VERSION 5.8 ;
BUSBITCHARS "[]" ;
DIVIDERCHAR "/" ;
UNITS
    DATABASE MICRONS 1000 ;
END UNITS

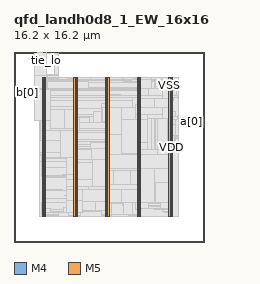
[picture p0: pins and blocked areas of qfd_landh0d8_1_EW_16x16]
MACRO qfd_landh0d8_1_EW_16x16
  FOREIGN qfd_landh0d8_1_EW_16x16 0 0 ;
  CLASS BLOCK ;
  SIZE 16.2 BY 16.2 ;
  PIN a[0]
    DIRECTION INPUT ;
    USE SIGNAL ;
    PORT
      LAYER M4 ;
        RECT  16.116 10.224 16.2 10.248 ;
    END
    PORT
      LAYER M4 ;
        RECT  15.397 10.224 16.14 10.248 ;
    END
  END a[0]
  PIN b[0]
    DIRECTION OUTPUT ;
    USE SIGNAL ;
    PORT
      LAYER M4 ;
        RECT  0 12.72 0.084 12.744 ;
    END
    PORT
      LAYER M4 ;
        RECT  0.06 12.72 1.861 12.744 ;
    END
  END b[0]
  PIN ck
    DIRECTION INPUT ;
    USE SIGNAL ;
    PORT
      LAYER M5 ;
        RECT  1.776 16.116 1.8 16.2 ;
    END
  END ck
  PIN ck_s
    DIRECTION INPUT ;
    USE SIGNAL ;
    PORT
      LAYER M5 ;
        RECT  1.872 16.116 1.896 16.2 ;
    END
  END ck_s
  PIN en
    DIRECTION INPUT ;
    USE SIGNAL ;
    PORT
      LAYER M5 ;
        RECT  1.968 16.116 1.992 16.2 ;
    END
  END en
  PIN fault
    DIRECTION OUTPUT ;
    USE SIGNAL ;
    PORT
      LAYER M5 ;
        RECT  2.064 16.116 2.088 16.2 ;
    END
  END fault
  PIN k0
    DIRECTION INPUT ;
    USE SIGNAL ;
    PORT
      LAYER M5 ;
        RECT  2.16 16.116 2.184 16.2 ;
    END
  END k0
  PIN k1
    DIRECTION INPUT ;
    USE SIGNAL ;
    PORT
      LAYER M5 ;
        RECT  2.256 16.116 2.28 16.2 ;
    END
  END k1
  PIN k2
    DIRECTION INPUT ;
    USE SIGNAL ;
    PORT
      LAYER M5 ;
        RECT  2.352 16.116 2.376 16.2 ;
    END
  END k2
  PIN k3
    DIRECTION INPUT ;
    USE SIGNAL ;
    PORT
      LAYER M5 ;
        RECT  2.448 16.116 2.472 16.2 ;
    END
  END k3
  PIN rs
    DIRECTION INPUT ;
    USE SIGNAL ;
    PORT
      LAYER M5 ;
        RECT  2.544 16.116 2.568 16.2 ;
    END
  END rs
  PIN tie_hi
    DIRECTION OUTPUT ;
    USE SIGNAL ;
    PORT
      LAYER M5 ;
        RECT  2.64 16.116 2.664 16.2 ;
    END
  END tie_hi
  PIN tie_lo
    DIRECTION OUTPUT ;
    USE SIGNAL ;
    PORT
      LAYER M5 ;
        RECT  2.736 16.116 2.76 16.2 ;
    END
  END tie_lo
  PIN VDD
    DIRECTION INOUT ;
    USE POWER ;
    PORT
      LAYER M5 ;
        RECT  13.392 2.151 13.512 14.049 ;
        RECT  10.692 2.151 10.812 14.049 ;
        RECT  7.992 2.151 8.112 14.049 ;
        RECT  5.292 2.151 5.412 14.049 ;
        RECT  2.592 2.151 2.712 14.049 ;
    END
  END VDD
  PIN VSS
    DIRECTION INOUT ;
    USE GROUND ;
    PORT
      LAYER M5 ;
        RECT  13.2 2.137 13.32 14.063 ;
        RECT  10.5 2.137 10.62 14.063 ;
        RECT  7.8 2.137 7.92 14.063 ;
        RECT  5.1 2.137 5.22 14.063 ;
        RECT  2.4 2.137 2.52 14.063 ;
    END
  END VSS
  # OT_OBS_CLOSED layer=M5 d_um=1.536 added=28
  OBS
    LAYER RVTN ;
     RECT  2.16 2.16 14.04 2.295 ;
     RECT  2.16 2.565 14.04 2.835 ;
     RECT  2.16 3.105 14.04 3.375 ;
     RECT  2.16 3.645 14.04 3.915 ;
     RECT  2.16 4.185 14.04 4.455 ;
     RECT  2.16 4.725 14.04 4.995 ;
     RECT  2.16 5.265 14.04 5.535 ;
     RECT  2.16 5.805 14.04 6.075 ;
     RECT  2.16 6.345 14.04 6.615 ;
     RECT  2.16 6.885 14.04 7.155 ;
     RECT  2.16 7.425 14.04 7.695 ;
     RECT  2.16 7.965 14.04 8.235 ;
     RECT  2.16 8.505 14.04 8.775 ;
     RECT  2.16 9.045 14.04 9.315 ;
     RECT  2.16 9.585 14.04 9.855 ;
     RECT  2.16 10.125 14.04 10.395 ;
     RECT  2.16 10.665 14.04 10.935 ;
     RECT  2.16 11.205 14.04 11.475 ;
     RECT  2.16 11.745 14.04 12.015 ;
     RECT  2.16 12.285 14.04 12.555 ;
     RECT  2.16 12.825 14.04 13.095 ;
     RECT  2.16 13.365 14.04 13.635 ;
     RECT  2.16 13.905 14.04 14.04 ;
    LAYER RVTP ;
     RECT  2.16 2.295 14.04 2.565 ;
     RECT  2.16 2.835 14.04 3.105 ;
     RECT  2.16 3.375 14.04 3.645 ;
     RECT  2.16 3.915 14.04 4.185 ;
     RECT  2.16 4.455 14.04 4.725 ;
     RECT  2.16 4.995 14.04 5.265 ;
     RECT  2.16 5.535 14.04 5.805 ;
     RECT  2.16 6.075 14.04 6.345 ;
     RECT  2.16 6.615 14.04 6.885 ;
     RECT  2.16 7.155 14.04 7.425 ;
     RECT  2.16 7.695 14.04 7.965 ;
     RECT  2.16 8.235 14.04 8.505 ;
     RECT  2.16 8.775 14.04 9.045 ;
     RECT  2.16 9.315 14.04 9.585 ;
     RECT  2.16 9.855 14.04 10.125 ;
     RECT  2.16 10.395 14.04 10.665 ;
     RECT  2.16 10.935 14.04 11.205 ;
     RECT  2.16 11.475 14.04 11.745 ;
     RECT  2.16 12.015 14.04 12.285 ;
     RECT  2.16 12.555 14.04 12.825 ;
     RECT  2.16 13.095 14.04 13.365 ;
     RECT  2.16 13.635 14.04 13.905 ;
    LAYER M1 ;
     RECT  2.16 2.151 14.04 14.049 ;
    LAYER M2 ;
     RECT  2.16 2.151 14.04 14.049 ;
     RECT  14.04 10.17 15.431 10.188 ;
    LAYER M3 ;
     RECT  2.415 2.143 2.505 2.191 ;
     RECT  5.115 2.143 5.205 2.191 ;
     RECT  10.515 2.143 10.605 2.191 ;
     RECT  5.115 2.191 5.634 2.227 ;
     RECT  7.815 2.143 7.905 2.227 ;
     RECT  10.224 2.191 10.605 2.227 ;
     RECT  2.415 2.191 2.574 2.299 ;
     RECT  3.816 2.227 3.834 2.299 ;
     RECT  7.488 2.227 8.154 2.299 ;
     RECT  2.415 2.299 3.834 2.371 ;
     RECT  9.756 2.227 10.605 2.413 ;
     RECT  13.215 2.143 13.305 2.413 ;
     RECT  2.376 2.371 3.834 2.491 ;
     RECT  13.215 2.413 13.497 2.533 ;
     RECT  12.816 2.533 13.497 2.569 ;
     RECT  2.376 2.491 3.942 2.641 ;
     RECT  4.68 2.227 5.634 2.641 ;
     RECT  6.732 2.605 6.75 2.641 ;
     RECT  7.488 2.299 8.334 2.641 ;
     RECT  9.756 2.413 10.797 2.641 ;
     RECT  9.72 2.641 10.797 2.731 ;
     RECT  12.636 2.569 13.497 2.731 ;
     RECT  2.376 2.641 8.334 2.759 ;
     RECT  9.72 2.731 10.854 2.839 ;
     RECT  9.504 2.839 10.854 2.875 ;
     RECT  11.988 2.731 13.497 2.875 ;
     RECT  9.396 2.875 13.497 3.001 ;
     RECT  9.324 3.001 13.497 3.073 ;
     RECT  9.252 3.073 13.497 3.307 ;
     RECT  2.376 2.759 8.298 3.371 ;
     RECT  9.144 3.307 13.497 3.685 ;
     RECT  2.415 3.371 8.298 3.721 ;
     RECT  9.036 3.685 13.497 3.721 ;
     RECT  2.415 3.721 13.497 4.379 ;
     RECT  11.988 4.379 13.497 4.685 ;
     RECT  12.06 4.685 13.497 4.721 ;
     RECT  12.348 4.721 13.497 4.757 ;
     RECT  2.415 4.379 11.214 5.503 ;
     RECT  2.415 5.503 11.394 5.539 ;
     RECT  2.415 5.539 11.79 5.575 ;
     RECT  2.34 5.575 11.79 5.707 ;
     RECT  12.564 4.757 13.497 5.707 ;
     RECT  2.34 5.707 13.497 6.317 ;
     RECT  2.34 6.317 11.25 6.853 ;
     RECT  2.196 6.853 11.25 6.893 ;
     RECT  2.415 6.893 11.25 7.147 ;
     RECT  12.06 6.317 13.497 7.147 ;
     RECT  2.415 7.147 13.497 7.349 ;
     RECT  4.572 7.349 13.497 7.591 ;
     RECT  4.572 7.591 13.554 7.735 ;
     RECT  2.415 7.349 3.798 8.167 ;
     RECT  4.572 7.735 13.662 8.167 ;
     RECT  2.415 8.167 13.662 8.339 ;
     RECT  10.008 8.339 13.662 8.401 ;
     RECT  2.415 8.339 9.27 8.539 ;
     RECT  2.34 8.539 9.27 8.544 ;
     RECT  2.337 8.544 9.27 8.733 ;
     RECT  2.34 8.733 9.27 8.735 ;
     RECT  10.008 8.401 13.734 8.851 ;
     RECT  10.008 8.851 13.914 8.969 ;
     RECT  10.116 8.969 13.914 9.101 ;
     RECT  2.415 8.735 9.27 9.355 ;
     RECT  2.415 9.355 9.378 9.499 ;
     RECT  2.34 9.499 9.378 9.509 ;
     RECT  2.34 9.509 8.154 9.689 ;
     RECT  8.964 9.509 9.378 9.979 ;
     RECT  10.116 9.101 13.806 9.979 ;
     RECT  8.964 9.979 13.806 10.049 ;
     RECT  8.964 10.049 9.378 10.121 ;
     RECT  15.408 10.165 15.426 10.253 ;
     RECT  10.332 10.049 13.806 10.471 ;
     RECT  2.34 9.689 8.097 10.633 ;
     RECT  10.332 10.471 13.914 10.661 ;
     RECT  2.34 10.633 8.226 10.705 ;
     RECT  8.964 10.121 9.198 10.705 ;
     RECT  2.304 10.705 9.198 10.843 ;
     RECT  10.332 10.661 13.806 11.129 ;
     RECT  2.304 10.843 9.414 11.405 ;
     RECT  2.34 11.405 9.414 11.407 ;
     RECT  10.332 11.129 13.497 11.407 ;
     RECT  2.34 11.407 13.497 12.091 ;
     RECT  2.34 12.091 13.59 12.361 ;
     RECT  2.34 12.361 13.914 12.515 ;
     RECT  2.34 12.515 13.842 12.901 ;
     RECT  2.304 12.901 13.842 13.008 ;
     RECT  2.301 13.008 13.842 13.089 ;
     RECT  2.304 13.089 13.842 13.163 ;
     RECT  2.415 13.163 13.842 13.559 ;
     RECT  2.415 13.559 13.497 13.787 ;
     RECT  2.415 13.787 13.305 13.829 ;
     RECT  10.044 13.829 13.305 13.853 ;
     RECT  6.48 13.829 6.714 13.865 ;
     RECT  10.188 13.853 13.305 13.865 ;
     RECT  4.572 13.829 5.205 13.901 ;
     RECT  6.48 13.865 6.498 13.901 ;
     RECT  9.288 13.829 9.306 13.901 ;
     RECT  10.188 13.865 10.605 13.901 ;
     RECT  11.7 13.865 11.718 13.901 ;
     RECT  2.415 13.829 3.762 13.945 ;
     RECT  2.268 13.945 3.762 13.997 ;
     RECT  4.644 13.901 5.205 14.009 ;
     RECT  12.6 13.865 13.305 14.009 ;
     RECT  2.415 13.997 3.762 14.057 ;
     RECT  5.115 14.009 5.205 14.057 ;
     RECT  7.815 13.829 7.905 14.057 ;
     RECT  10.515 13.901 10.605 14.057 ;
     RECT  13.215 14.009 13.305 14.057 ;
     RECT  2.556 14.057 3.762 14.237 ;
     RECT  2.628 14.237 3.762 14.285 ;
     RECT  2.628 14.285 2.646 14.861 ;
     RECT  3.42 14.285 3.762 16.061 ;
     RECT  3.42 16.061 3.438 16.109 ;
    LAYER M4 ;
     RECT  1.861 12.72 1.957 13.032 ;
     RECT  2.149 7.392 2.185 7.416 ;
     RECT  1.765 10.368 2.245 10.392 ;
     RECT  2.101 11.376 2.245 11.4 ;
     RECT  2.149 8.64 2.293 8.664 ;
     RECT  2.293 8.544 2.329 8.664 ;
     RECT  2.245 10.368 2.329 11.4 ;
     RECT  1.957 12.72 2.329 13.992 ;
     RECT  2.329 12.528 2.341 13.992 ;
     RECT  2.365 2.496 2.408 2.52 ;
     RECT  2.185 6.864 2.408 7.416 ;
     RECT  2.329 8.544 2.408 11.4 ;
     RECT  2.341 12.528 2.408 14.184 ;
     RECT  2.408 2.148 2.437 14.184 ;
     RECT  2.437 2.148 2.512 14.232 ;
     RECT  2.053 16.08 2.533 16.104 ;
     RECT  2.512 2.418 2.617 14.232 ;
     RECT  2.617 2.418 2.675 14.856 ;
     RECT  2.675 2.418 2.704 14.28 ;
     RECT  2.704 12.528 2.771 14.28 ;
     RECT  2.771 12.528 2.819 14.184 ;
     RECT  2.704 2.496 3.125 2.856 ;
     RECT  2.533 16.032 3.449 16.104 ;
     RECT  3.449 16.032 3.773 16.056 ;
     RECT  2.704 7.2 3.841 7.704 ;
     RECT  3.841 7.2 3.971 8.52 ;
     RECT  2.704 4.416 4.097 4.44 ;
     RECT  3.125 2.496 4.237 2.52 ;
     RECT  4.237 2.496 4.453 2.904 ;
     RECT  4.345 3.936 4.453 3.96 ;
     RECT  4.129 5.76 4.633 5.784 ;
     RECT  4.633 5.76 4.993 6.12 ;
     RECT  3.971 7.2 4.993 7.701 ;
     RECT  4.993 5.76 5.029 7.701 ;
     RECT  2.819 13.056 5.101 13.704 ;
     RECT  4.453 2.496 5.108 3.96 ;
     RECT  5.029 5.04 5.108 7.701 ;
     RECT  2.704 9.504 5.108 11.544 ;
     RECT  5.101 12.528 5.108 13.704 ;
     RECT  5.108 2.148 5.212 14.052 ;
     RECT  5.212 2.418 5.404 13.782 ;
     RECT  5.404 9.504 5.573 10.632 ;
     RECT  5.404 2.496 5.891 7.848 ;
     RECT  5.891 2.64 5.897 7.848 ;
     RECT  5.404 13.104 6.329 13.656 ;
     RECT  5.573 10.176 6.433 10.632 ;
     RECT  5.897 4.512 6.473 7.848 ;
     RECT  6.473 4.56 6.505 7.848 ;
     RECT  6.433 10.176 6.793 10.728 ;
     RECT  5.897 2.64 6.901 3.336 ;
     RECT  6.901 2.64 7.405 3.432 ;
     RECT  6.793 10.176 7.441 11.16 ;
     RECT  7.405 2.64 7.477 3.576 ;
     RECT  6.505 4.56 7.801 8.472 ;
     RECT  7.477 2.304 7.808 3.576 ;
     RECT  7.801 4.56 7.808 8.568 ;
     RECT  7.441 10.176 7.808 11.784 ;
     RECT  6.329 13.104 7.808 13.128 ;
     RECT  7.808 2.148 7.912 14.052 ;
     RECT  7.912 2.304 8.104 13.782 ;
     RECT  8.104 4.512 8.531 9.144 ;
     RECT  8.531 4.656 9.065 9.144 ;
     RECT  8.104 12.528 9.065 12.552 ;
     RECT  8.104 10.704 9.097 10.728 ;
     RECT  9.097 9.936 9.133 10.728 ;
     RECT  9.133 9.936 9.157 10.872 ;
     RECT  9.157 9.936 9.245 11.448 ;
     RECT  8.104 2.304 9.313 2.328 ;
     RECT  8.104 3.312 9.313 3.432 ;
     RECT  9.245 9.984 9.425 11.448 ;
     RECT  9.313 13.68 10.033 13.704 ;
     RECT  9.313 2.304 10.117 3.432 ;
     RECT  9.065 4.656 10.117 8.856 ;
     RECT  9.425 11.424 10.141 11.448 ;
     RECT  10.117 2.304 10.508 8.856 ;
     RECT  9.425 9.984 10.508 10.44 ;
     RECT  10.141 11.424 10.508 12.36 ;
     RECT  10.033 13.68 10.508 13.848 ;
     RECT  10.508 2.148 10.612 14.052 ;
     RECT  10.612 2.418 10.804 13.848 ;
     RECT  10.804 2.88 11.477 3.624 ;
     RECT  10.804 5.76 11.729 13.848 ;
     RECT  11.729 5.76 11.989 13.704 ;
     RECT  11.989 5.712 12.035 13.704 ;
     RECT  12.035 5.712 12.229 11.112 ;
     RECT  11.477 3.36 12.517 3.624 ;
     RECT  12.517 2.832 13.208 3.624 ;
     RECT  12.229 5.088 13.208 11.112 ;
     RECT  12.035 12.144 13.208 13.704 ;
     RECT  13.208 2.148 13.312 14.052 ;
     RECT  13.312 2.418 13.504 13.782 ;
     RECT  13.504 7.92 13.673 9.096 ;
     RECT  13.673 8.448 13.745 9.096 ;
     RECT  13.745 9.072 13.925 9.096 ;
    LAYER M5 ;
     RECT  2.4 2.137 2.52 2.151 ;
     RECT  5.1 2.137 5.22 2.151 ;
     RECT  7.8 2.137 7.92 2.151 ;
     RECT  10.5 2.137 10.62 2.151 ;
     RECT  13.2 2.137 13.32 2.151 ;
     RECT  5.1 2.151 5.412 2.485 ;
     RECT  7.8 2.151 8.112 2.677 ;
     RECT  10.5 2.151 10.812 2.773 ;
     RECT  10.368 2.773 10.812 3.397 ;
     RECT  6.912 2.677 8.112 3.443 ;
     RECT  4.464 2.485 5.88 3.539 ;
     RECT  4.512 3.539 5.88 4.501 ;
     RECT  7.8 3.443 8.112 4.501 ;
     RECT  9.168 3.397 10.812 4.501 ;
     RECT  4.512 4.501 6.312 4.741 ;
     RECT  7.8 4.501 10.812 4.883 ;
     RECT  12 3.349 12.024 5.077 ;
     RECT  13.2 2.151 13.512 5.077 ;
     RECT  4.512 4.741 6.696 5.363 ;
     RECT  4.512 5.363 5.412 5.795 ;
     RECT  7.8 4.883 8.52 6.085 ;
     RECT  9.936 4.883 10.812 6.085 ;
     RECT  7.8 6.085 10.812 6.277 ;
     RECT  12 5.077 13.512 6.277 ;
     RECT  5.1 5.795 5.412 6.805 ;
     RECT  6.672 5.363 6.696 6.805 ;
     RECT  2.4 2.151 2.712 6.853 ;
     RECT  5.1 6.805 6.696 6.995 ;
     RECT  2.304 6.853 2.712 7.381 ;
     RECT  2.16 7.381 2.712 7.427 ;
     RECT  7.8 6.277 13.512 7.427 ;
     RECT  7.8 7.427 10.812 7.475 ;
     RECT  10.224 7.475 10.812 7.523 ;
     RECT  2.163 7.427 2.712 7.669 ;
     RECT  3.936 7.189 3.96 7.669 ;
     RECT  5.1 6.995 6.648 7.859 ;
     RECT  12.24 7.427 13.512 7.907 ;
     RECT  6.624 7.859 6.648 7.955 ;
     RECT  10.5 7.523 10.812 8.485 ;
     RECT  2.163 7.669 3.96 8.629 ;
     RECT  2.16 8.629 3.96 8.675 ;
     RECT  7.8 7.475 9.192 9.155 ;
     RECT  2.259 8.675 3.96 9.539 ;
     RECT  5.1 7.859 5.412 9.637 ;
     RECT  7.8 9.155 8.112 10.261 ;
     RECT  2.259 9.539 3.141 10.357 ;
     RECT  10.5 8.485 11.4 10.405 ;
     RECT  13.104 7.907 13.512 10.501 ;
     RECT  10.368 10.405 11.4 10.883 ;
     RECT  4.32 9.637 5.412 11.267 ;
     RECT  7.584 10.261 8.112 11.459 ;
     RECT  9.168 9.155 9.192 11.459 ;
     RECT  12.672 10.501 13.512 11.509 ;
     RECT  10.368 10.883 10.812 11.747 ;
     RECT  12 11.509 13.512 12.275 ;
     RECT  10.5 11.747 10.812 12.517 ;
     RECT  1.776 10.357 3.141 13.045 ;
     RECT  1.776 13.045 3.144 13.091 ;
     RECT  10.5 12.517 11.448 13.091 ;
     RECT  12.672 12.275 13.512 13.715 ;
     RECT  5.1 11.267 5.412 14.049 ;
     RECT  7.8 11.459 8.112 14.049 ;
     RECT  10.5 13.091 10.812 14.049 ;
     RECT  13.2 13.715 13.512 14.049 ;
     RECT  5.1 14.049 5.22 14.063 ;
     RECT  7.8 14.049 7.92 14.063 ;
     RECT  10.5 14.049 10.62 14.063 ;
     RECT  13.2 14.049 13.32 14.063 ;
     RECT  1.776 13.091 2.808 14.195 ;
     RECT  1.776 14.195 2.76 16.116 ;
     RECT  1.8 16.116 1.872 16.144 ;
     RECT  1.896 16.116 1.968 16.144 ;
     RECT  1.992 16.116 2.064 16.144 ;
     RECT  2.088 16.116 2.16 16.144 ;
     RECT  2.184 16.116 2.256 16.144 ;
     RECT  2.28 16.116 2.352 16.144 ;
     RECT  2.376 16.116 2.448 16.144 ;
     RECT  2.472 16.116 2.544 16.144 ;
     RECT  2.568 16.116 2.64 16.144 ;
     RECT  2.664 16.116 2.736 16.144 ;
     RECT  5.88 2.677 6.912 3.443 ;
     RECT  10.812 3.349 12 6.277 ;
     RECT  12.024 3.349 13.2 5.077 ;
     RECT  8.112 3.397 9.168 4.501 ;
     RECT  5.88 3.443 7.8 4.501 ;
     RECT  6.312 4.501 7.8 4.741 ;
     RECT  6.696 4.741 7.8 6.995 ;
     RECT  8.52 4.883 9.936 6.085 ;
     RECT  5.412 5.363 6.672 6.805 ;
     RECT  4.512 5.795 5.1 7.189 ;
     RECT  6.648 6.995 7.8 7.955 ;
     RECT  2.712 7.189 3.936 7.669 ;
     RECT  3.96 7.189 5.1 9.539 ;
     RECT  2.16 7.427 2.163 8.629 ;
     RECT  10.812 7.427 12.24 7.907 ;
     RECT  9.192 7.475 10.224 7.523 ;
     RECT  9.192 7.523 10.5 10.405 ;
     RECT  5.412 7.859 6.624 7.955 ;
     RECT  10.812 7.907 11.4 8.485 ;
     RECT  8.112 9.155 9.168 11.459 ;
     RECT  3.141 9.539 5.1 9.637 ;
     RECT  3.141 9.637 4.32 11.267 ;
     RECT  9.192 10.405 10.368 11.459 ;
     RECT  11.4 10.501 12.672 10.883 ;
     RECT  10.812 10.883 12.672 11.509 ;
     RECT  10.812 11.509 12 12.275 ;
     RECT  10.812 12.275 12.672 12.517 ;
     RECT  11.448 12.517 12.672 13.091 ;
  END
END qfd_landh0d8_1_EW_16x16
END LIBRARY
